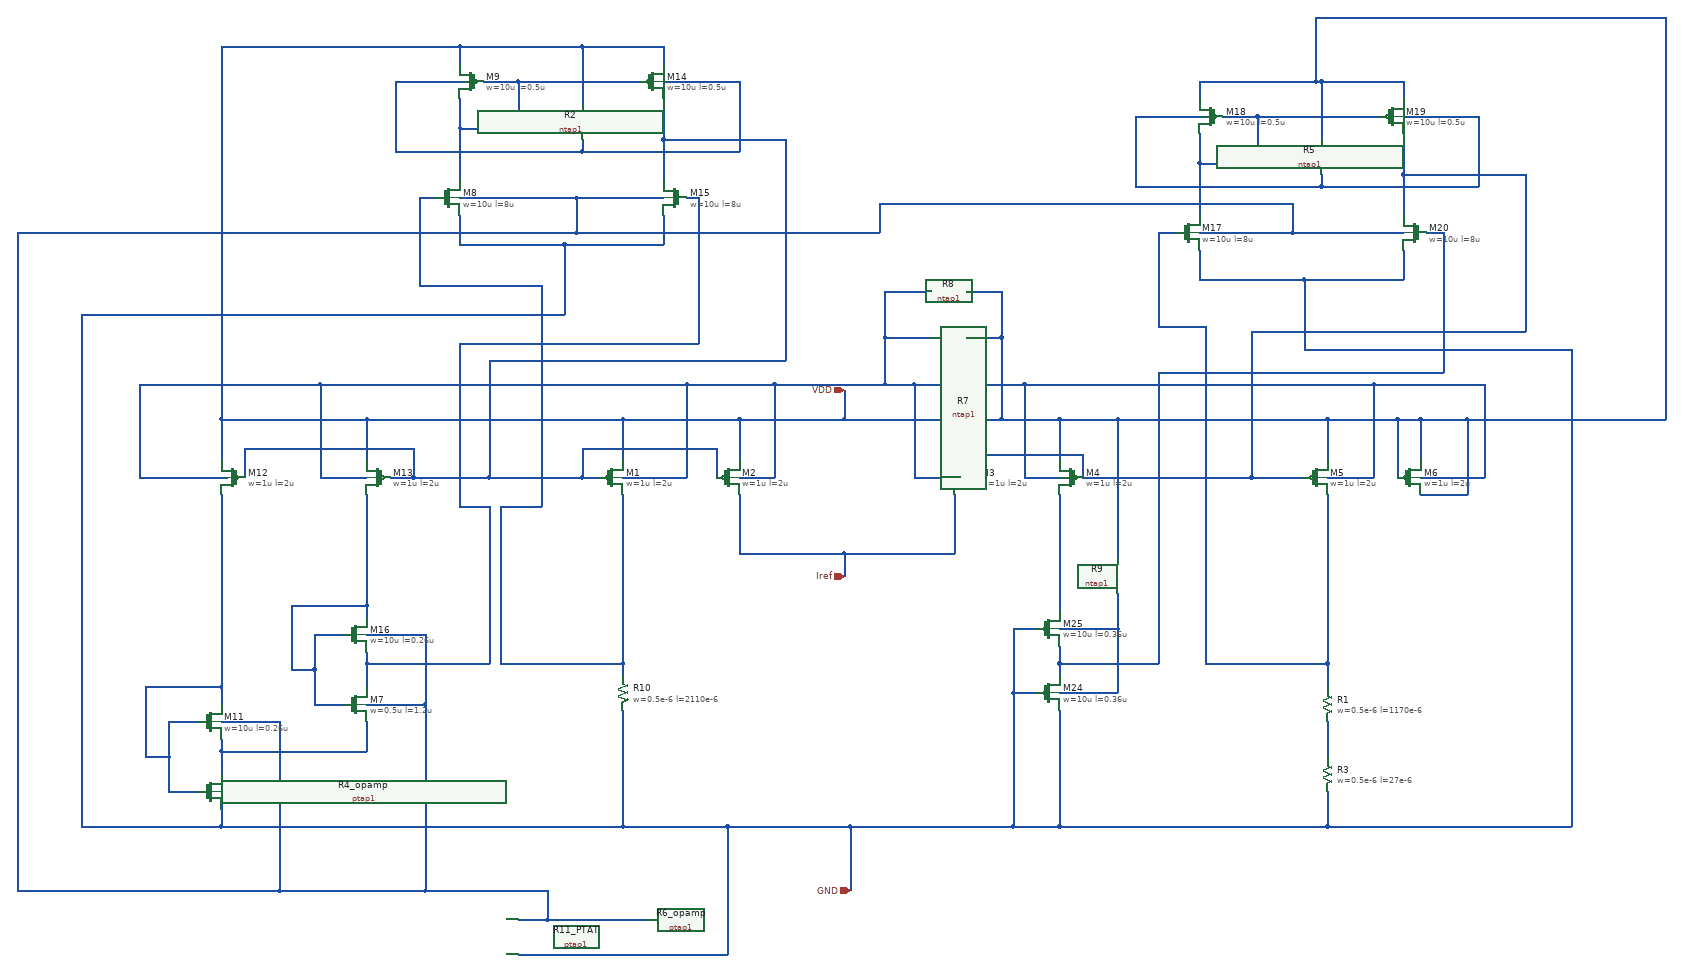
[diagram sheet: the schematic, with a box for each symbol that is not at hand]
v {xschem version=3.4.6 file_version=1.2}
G {}
K {}
V {}
S {}
E {}
N 1760 -790 1760 -750 {lab=#net1}
N 1640 -490 1680 -490 {lab=GND}
N 1640 -380 1680 -380 {lab=GND}
N 1720 -430 1720 -410 {lab=#net2}
N 530 -850 970 -850 {lab=VDD}
N 900 -750 930 -750 {lab=#net3}
N 900 -800 900 -750 {lab=#net3}
N 1130 -800 1130 -750 {lab=#net3}
N 1580 -790 1580 -750 {lab=#net1}
N 530 -430 530 -390 {lab=#net4}
N 530 -480 630 -480 {lab=#net5}
N 630 -480 630 -360 {lab=#net5}
N 530 -360 630 -360 {lab=#net5}
N 440 -480 490 -480 {lab=#net6}
N 440 -420 440 -360 {lab=#net6}
N 440 -360 490 -360 {lab=#net6}
N 530 -530 530 -510 {lab=#net6}
N 400 -420 440 -420 {lab=#net6}
N 440 -480 440 -420 {lab=#net6}
N 400 -530 400 -420 {lab=#net6}
N 400 -530 530 -530 {lab=#net6}
N 530 -720 530 -530 {lab=#net6}
N 530 -430 740 -430 {lab=#net4}
N 530 -450 530 -430 {lab=#net4}
N 280 -280 280 -240 {lab=#net7}
N 280 -330 380 -330 {lab=#net5}
N 380 -330 380 -210 {lab=#net5}
N 280 -210 380 -210 {lab=#net5}
N 190 -330 240 -330 {lab=#net8}
N 190 -270 190 -210 {lab=#net8}
N 190 -210 240 -210 {lab=#net8}
N 150 -270 190 -270 {lab=#net8}
N 190 -330 190 -270 {lab=#net8}
N 280 -280 530 -280 {lab=#net7}
N 280 -300 280 -280 {lab=#net7}
N 530 -330 530 -280 {lab=#net7}
N 280 -390 280 -360 {lab=#net8}
N 320 -800 610 -800 {lab=#net3}
N 610 -800 610 -750 {lab=#net3}
N 570 -750 610 -750 {lab=#net3}
N 280 -190 280 -150 {lab=GND}
N 150 -390 150 -270 {lab=#net8}
N 150 -390 280 -390 {lab=#net8}
N 280 -720 280 -390 {lab=#net8}
N 1640 -490 1640 -380 {lab=GND}
N 280 -150 970 -150 {lab=GND}
N 970 -430 970 -410 {lab=#net9}
N 970 -350 970 -150 {lab=GND}
N 760 -430 970 -430 {lab=#net9}
N 970 -720 970 -430 {lab=#net9}
N 2180 -720 2180 -430 {lab=#net10}
N 1720 -720 1720 -520 {lab=#net11}
N 1720 -350 1720 -150 {lab=GND}
N 1720 -460 1720 -430 {lab=#net2}
N 1720 -150 2180 -150 {lab=GND}
N 1640 -150 1720 -150 {lab=GND}
N 1640 -380 1640 -150 {lab=GND}
N 1170 -720 1170 -620 {lab=Iref}
N 1540 -720 1540 -620 {lab=Iref}
N 1350 -900 1350 -850 {lab=VDD}
N 1360 -150 1640 -150 {lab=GND}
N 1360 -150 1360 -40 {lab=GND}
N 1820 -850 2180 -850 {lab=VDD}
N 320 -800 320 -750 {lab=#net3}
N 900 -800 1130 -800 {lab=#net3}
N 1580 -790 1760 -790 {lab=#net1}
N 1350 -620 1540 -620 {lab=Iref}
N 1760 -750 2050 -750 {lab=#net1}
N 740 -750 900 -750 {lab=#net3}
N 1970 -430 2180 -430 {lab=#net10}
N 1720 -490 1820 -490 {lab=#net12}
N 1720 -380 1820 -380 {lab=#net12}
N 2050 -750 2140 -750 {lab=#net1}
N 2180 -430 2180 -390 {lab=#net10}
N 2180 -210 2180 -150 {lab=GND}
N 2180 -850 2180 -780 {lab=VDD}
N 2340 -850 2340 -780 {lab=VDD}
N 2300 -850 2340 -850 {lab=VDD}
N 2300 -850 2300 -750 {lab=VDD}
N 2180 -850 2300 -850 {lab=VDD}
N 2340 -720 2420 -720 {lab=VDD}
N 2340 -850 2420 -850 {lab=VDD}
N 2420 -850 2420 -720 {lab=VDD}
N 1350 -620 1350 -580 {lab=Iref}
N 1170 -620 1350 -620 {lab=Iref}
N 380 -210 380 -40 {lab=#net5}
N 380 -40 630 -40 {lab=#net5}
N 630 -360 630 -40 {lab=#net5}
N 2180 -330 2180 -270 {lab=#net13}
N 1150 -150 1360 -150 {lab=GND}
N 1170 -850 1170 -780 {lab=VDD}
N 970 -850 1170 -850 {lab=VDD}
N 970 -850 970 -780 {lab=VDD}
N 530 -850 530 -780 {lab=VDD}
N 280 -850 530 -850 {lab=VDD}
N 280 -850 280 -780 {lab=VDD}
N 140 -750 290 -750 {lab=#net14}
N 140 -910 140 -750 {lab=#net14}
N 1080 -910 1230 -910 {lab=#net14}
N 1230 -910 1230 -750 {lab=#net14}
N 1170 -750 1230 -750 {lab=#net14}
N 450 -750 530 -750 {lab=#net14}
N 450 -910 450 -750 {lab=#net14}
N 140 -910 450 -910 {lab=#net14}
N 970 -750 1080 -750 {lab=#net14}
N 1080 -910 1080 -750 {lab=#net14}
N 450 -910 1080 -910 {lab=#net14}
N 1470 -750 1550 -750 {lab=#net14}
N 1470 -910 1470 -750 {lab=#net14}
N 2260 -910 2450 -910 {lab=#net14}
N 2450 -910 2450 -750 {lab=#net14}
N 2340 -750 2450 -750 {lab=#net14}
N 2180 -750 2260 -750 {lab=#net14}
N 2260 -910 2260 -750 {lab=#net14}
N 1660 -910 2260 -910 {lab=#net14}
N 1540 -850 1540 -780 {lab=VDD}
N 1350 -850 1540 -850 {lab=VDD}
N 1720 -850 1720 -780 {lab=VDD}
N 1620 -850 1720 -850 {lab=VDD}
N 1660 -750 1730 -750 {lab=#net14}
N 1660 -910 1660 -750 {lab=#net14}
N 1470 -910 1660 -910 {lab=#net14}
N 1420 -910 1470 -910 {lab=#net14}
N 1170 -850 1350 -850 {lab=VDD}
N 790 -1430 1000 -1430 {lab=#net15}
N 690 -1350 790 -1350 {lab=#net15}
N 690 -1400 690 -1350 {lab=#net15}
N 790 -1430 790 -1350 {lab=#net15}
N 730 -1430 790 -1430 {lab=#net15}
N 690 -1200 690 -1150 {lab=GND}
N 900 -1490 1040 -1490 {lab=VDD}
N 620 -1230 650 -1230 {lab=#net9}
N 690 -1350 690 -1260 {lab=#net15}
N 890 -1230 1040 -1230 {lab=#net5}
N 690 -1150 870 -1150 {lab=GND}
N 870 -1150 870 -1030 {lab=GND}
N 690 -1490 900 -1490 {lab=VDD}
N 1040 -1330 1040 -1260 {lab=#net3}
N 1040 -1200 1040 -1150 {lab=GND}
N 1040 -1490 1040 -1450 {lab=VDD}
N 690 -1490 690 -1460 {lab=VDD}
N 580 -1430 700 -1430 {lab=#net16}
N 580 -1430 580 -1310 {lab=#net16}
N 580 -1310 900 -1310 {lab=#net16}
N 900 -1330 900 -1310 {lab=#net16}
N 900 -1310 1170 -1310 {lab=#net16}
N 1170 -1430 1170 -1310 {lab=#net16}
N 1040 -1430 1170 -1430 {lab=#net16}
N 900 -1490 900 -1390 {lab=VDD}
N 870 -1150 1040 -1150 {lab=GND}
N 40 -1030 870 -1030 {lab=GND}
N 40 -150 280 -150 {lab=GND}
N 40 -1030 40 -150 {lab=GND}
N 280 -1490 280 -850 {lab=VDD}
N 280 -1490 690 -1490 {lab=VDD}
N 1040 -1330 1250 -1330 {lab=#net3}
N 1040 -1400 1040 -1330 {lab=#net3}
N 1250 -1330 1250 -950 {lab=#net3}
N 740 -950 1250 -950 {lab=#net3}
N 740 -950 740 -750 {lab=#net3}
N 610 -750 740 -750 {lab=#net3}
N 740 -700 740 -430 {lab=#net4}
N 690 -700 740 -700 {lab=#net4}
N 690 -980 690 -700 {lab=#net4}
N 690 -980 1100 -980 {lab=#net4}
N 1100 -1230 1100 -980 {lab=#net4}
N 1080 -1230 1100 -1230 {lab=#net4}
N 760 -700 760 -430 {lab=#net9}
N 760 -700 830 -700 {lab=#net9}
N 830 -1080 830 -700 {lab=#net9}
N 620 -1080 830 -1080 {lab=#net9}
N 620 -1230 620 -1080 {lab=#net9}
N 2060 -1370 2270 -1370 {lab=#net17}
N 1960 -1290 2060 -1290 {lab=#net17}
N 1960 -1340 1960 -1290 {lab=#net17}
N 2060 -1370 2060 -1290 {lab=#net17}
N 2000 -1370 2060 -1370 {lab=#net17}
N 1960 -1140 1960 -1090 {lab=GND}
N 2170 -1430 2310 -1430 {lab=VDD}
N 1890 -1170 1920 -1170 {lab=#net10}
N 1960 -1290 1960 -1200 {lab=#net17}
N 2120 -1170 2310 -1170 {lab=#net5}
N 1960 -1090 2140 -1090 {lab=GND}
N 2140 -1090 2140 -970 {lab=GND}
N 2160 -1430 2170 -1430 {lab=VDD}
N 2310 -1270 2310 -1200 {lab=#net1}
N 2310 -1140 2310 -1090 {lab=GND}
N 2350 -1170 2380 -1170 {lab=#net2}
N 2310 -1430 2310 -1390 {lab=VDD}
N 1960 -1430 1960 -1400 {lab=VDD}
N 1850 -1370 1970 -1370 {lab=#net18}
N 1850 -1370 1850 -1250 {lab=#net18}
N 1850 -1250 2170 -1250 {lab=#net18}
N 2170 -1270 2170 -1250 {lab=#net18}
N 2170 -1250 2440 -1250 {lab=#net18}
N 2440 -1370 2440 -1250 {lab=#net18}
N 2310 -1370 2440 -1370 {lab=#net18}
N 2170 -1430 2170 -1330 {lab=VDD}
N 2140 -1090 2310 -1090 {lab=GND}
N 2140 -970 2600 -970 {lab=GND}
N 2180 -150 2600 -150 {lab=GND}
N 2600 -970 2600 -150 {lab=GND}
N 2420 -850 2760 -850 {lab=VDD}
N 2760 -1540 2760 -850 {lab=VDD}
N 2160 -1540 2760 -1540 {lab=VDD}
N 2160 -1540 2160 -1430 {lab=VDD}
N 1960 -1430 2160 -1430 {lab=VDD}
N 2380 -1170 2380 -930 {lab=#net2}
N 1890 -930 2380 -930 {lab=#net2}
N 1890 -930 1890 -430 {lab=#net2}
N 1720 -430 1890 -430 {lab=#net2}
N 2310 -1270 2520 -1270 {lab=#net1}
N 2310 -1340 2310 -1270 {lab=#net1}
N 2520 -1270 2520 -1000 {lab=#net1}
N 2050 -1000 2520 -1000 {lab=#net1}
N 2050 -1000 2050 -750 {lab=#net1}
N 1970 -1010 1970 -430 {lab=#net10}
N 1890 -1010 1970 -1010 {lab=#net10}
N 1890 -1170 1890 -1010 {lab=#net10}
N 1420 -990 1500 -990 {lab=#net14}
N 1420 -990 1420 -910 {lab=#net14}
N 1230 -910 1420 -910 {lab=#net14}
N 1560 -990 1620 -990 {lab=VDD}
N 1620 -990 1620 -850 {lab=VDD}
N 1540 -850 1620 -850 {lab=VDD}
N 1420 -1070 1500 -1070 {lab=#net14}
N 1420 -1070 1420 -990 {lab=#net14}
N 1560 -1070 1620 -1070 {lab=VDD}
N 1620 -1070 1620 -990 {lab=VDD}
N 1820 -490 1820 -380 {lab=#net12}
N 1820 -550 1820 -490 {lab=#net12}
N 1820 -850 1820 -610 {lab=VDD}
N 1720 -850 1820 -850 {lab=VDD}
N 840 10 1010 10 {lab=#net5}
N 630 -40 840 -40 {lab=#net5}
N 840 -40 840 10 {lab=#net5}
N 790 10 840 10 {lab=#net5}
N 790 70 1150 70 {lab=GND}
N 1150 -150 1150 70 {lab=GND}
N 970 -150 1150 -150 {lab=GND}
N 2120 -1220 2120 -1170 {lab=#net5}
N 1960 -1170 2120 -1170 {lab=#net5}
N 1410 -1220 2120 -1220 {lab=#net5}
N 1410 -1220 1410 -1170 {lab=#net5}
N 890 -1170 1410 -1170 {lab=#net5}
N 890 -1230 890 -1170 {lab=#net5}
N 690 -1230 890 -1230 {lab=#net5}
N -70 -1170 890 -1170 {lab=#net5}
N -70 -1170 -70 -40 {lab=#net5}
N -70 -40 380 -40 {lab=#net5}
C {iopin.sym} 1350 -900 0 0 {name=p1 lab=VDD}
C {iopin.sym} 1360 -40 0 0 {name=p2 lab=GND}
C {sg13g2_pr/sg13_lv_pmos.sym} 950 -750 0 0 {name=M1
l=2u
w=1u
ng=1
m=1
model=sg13_lv_pmos
spiceprefix=X
}
C {sg13g2_pr/sg13_lv_pmos.sym} 1150 -750 0 0 {name=M2
l=2u
w=1u
ng=1
m=6
model=sg13_lv_pmos
spiceprefix=X
}
C {sg13g2_pr/sg13_lv_pmos.sym} 1560 -750 0 1 {name=M3
l=2u
w=1u
ng=1
m=6
model=sg13_lv_pmos
spiceprefix=X
}
C {sg13g2_pr/sg13_lv_pmos.sym} 1740 -750 0 1 {name=M4
l=2u
w=1u
ng=1
m=1
model=sg13_lv_pmos
spiceprefix=X
}
C {sg13g2_pr/sg13_lv_pmos.sym} 300 -750 0 1 {name=M12
l=2u
w=1u
ng=1
m=1
model=sg13_lv_pmos
spiceprefix=X
}
C {sg13g2_pr/sg13_lv_pmos.sym} 550 -750 0 1 {name=M13
l=2u
w=1u
ng=1
m=1
model=sg13_lv_pmos
spiceprefix=X
}
C {sg13g2_pr/sg13_lv_pmos.sym} 2160 -750 0 0 {name=M5
l=2u
w=1u
ng=1
m=1
model=sg13_lv_pmos
spiceprefix=X
}
C {sg13g2_pr/sg13_lv_nmos.sym} 510 -360 0 0 {name=M7
l=1.2u
w=0.5u
ng=1
m=1
model=sg13_lv_nmos
spiceprefix=X
}
C {sg13g2_pr/sg13_lv_nmos.sym} 260 -210 0 0 {name=M10
l=1.2u
w=0.5u
ng=1
m=1
model=sg13_lv_nmos
spiceprefix=X
}
C {sg13g2_pr/sg13_lv_nmos.sym} 260 -330 0 0 {name=M11
l=0.26u
w=10u
ng=1
m=30
model=sg13_lv_nmos
spiceprefix=X
}
C {sg13g2_pr/sg13_lv_nmos.sym} 510 -480 0 0 {name=M16
l=0.26u
w=10u
ng=1
m=30
model=sg13_lv_nmos
spiceprefix=X
}
C {sg13g2_pr/sg13_lv_pmos.sym} 1700 -380 0 0 {name=M24
l=0.36u
w=10u
ng=1
m=20
model=sg13_lv_pmos
spiceprefix=X
}
C {sg13g2_pr/sg13_lv_pmos.sym} 1700 -490 0 0 {name=M25
l=0.36u
w=10u
ng=1
m=1
model=sg13_lv_pmos
spiceprefix=X
}
C {sg13g2_pr/rppd.sym} 2180 -360 0 0 {name=R1
w=0.5e-6
l=1170e-6
model=rppd
body=GND
spiceprefix=X
b=0
m=1
}
C {sg13g2_pr/rhigh.sym} 2180 -240 0 0 {name=R3
w=0.5e-6
l=27e-6
model=rhigh
body=GND
spiceprefix=X
b=0
m=1
}
C {sg13g2_pr/rppd.sym} 970 -380 0 0 {name=R10
w=0.5e-6
l=2110e-6
model=rppd
body=GND
spiceprefix=X
b=0
m=1
}
C {sg13g2_pr/sg13_lv_pmos.sym} 2320 -750 0 0 {name=M6
l=2u
w=1u
ng=1
m=1
model=sg13_lv_pmos
spiceprefix=X
}
C {iopin.sym} 1350 -580 0 0 {name=p3 lab=Iref}
C {sg13g2_pr/sg13_lv_nmos.sym} 670 -1230 0 0 {name=M8
l=8u
w=10u
ng=1
m=6
model=sg13_lv_nmos
spiceprefix=X
}
C {sg13g2_pr/sg13_lv_pmos.sym} 710 -1430 0 1 {name=M9
l=0.5u
w=10u
ng=1
m=4
model=sg13_lv_pmos
spiceprefix=X
}
C {sg13g2_pr/sg13_lv_pmos.sym} 1020 -1430 0 0 {name=M14
l=0.5u
w=10u
ng=1
m=4
model=sg13_lv_pmos
spiceprefix=X
}
C {sg13g2_pr/sg13_lv_nmos.sym} 1060 -1230 0 1 {name=M15
l=8u
w=10u
ng=1
m=6
model=sg13_lv_nmos
spiceprefix=X
}
C {sg13g2_pr/ntap1.sym} 900 -1360 0 1 {name=R2
model=ntap1
spiceprefix=X
w=1e-6
l=20e-6
}
C {sg13g2_pr/ptap1.sym} 790 40 2 0 {name=R4_opamp
model=ptap1
spiceprefix=X
w=56e-6
l=1e-6
}
C {sg13g2_pr/sg13_lv_nmos.sym} 1940 -1170 0 0 {name=M17
l=8u
w=10u
ng=1
m=6
model=sg13_lv_nmos
spiceprefix=X
}
C {sg13g2_pr/sg13_lv_pmos.sym} 1980 -1370 0 1 {name=M18
l=0.5u
w=10u
ng=1
m=4
model=sg13_lv_pmos
spiceprefix=X
}
C {sg13g2_pr/sg13_lv_pmos.sym} 2290 -1370 0 0 {name=M19
l=0.5u
w=10u
ng=1
m=4
model=sg13_lv_pmos
spiceprefix=X
}
C {sg13g2_pr/sg13_lv_nmos.sym} 2330 -1170 0 1 {name=M20
l=8u
w=10u
ng=1
m=6
model=sg13_lv_nmos
spiceprefix=X
}
C {sg13g2_pr/ntap1.sym} 2170 -1300 0 1 {name=R5
model=ntap1
spiceprefix=X
w=1e-6
l=20e-6
}
C {sg13g2_pr/ptap1.sym} 1010 40 2 0 {name=R6_opamp
model=ptap1
spiceprefix=X
w=56e-6
l=1e-6
}
C {sg13g2_pr/ntap1.sym} 1530 -990 1 0 {name=R7
model=ntap1
spiceprefix=X
w=5e-6
l=1e-6
}
C {sg13g2_pr/ntap1.sym} 1530 -1070 1 0 {name=R8
model=ntap1
spiceprefix=X
w=5e-6
l=1e-6
}
C {sg13g2_pr/ntap1.sym} 1820 -580 0 1 {name=R9
model=ntap1
spiceprefix=X
w=1e-6
l=8e-6
}
C {sg13g2_pr/ptap1.sym} 890 40 2 0 {name=R11_PTAT
model=ptap1
spiceprefix=X
w=1e-6
l=19e-6
}
